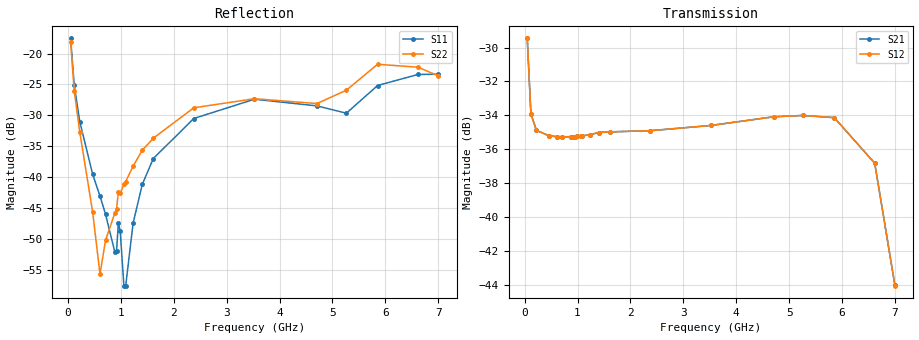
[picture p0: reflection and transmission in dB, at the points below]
! Integrated Device Technology
! Corporate Headquarters
! 6024 Silver Creek Valley Road
! San Jose, CA 95138  USA
! Phone:  1-408-284-8200
! Toll Free:  1-800-223-1366
! Webpage:  http://www.idt.com/
! Timing and RF Division
! 515 Groton Road, Suite 102
! Westford, MA 01886-6024
! Device:  F2258
! Description: Voltage Variable RF Attenuator
! Frequency:  50.0 -  6000.00 MHz
! Package:  3x3 mm Thin QFN Plastic Package: 16 pin
! Ports:  2 RF, 2 DC
!  Pin  1  = NC
!  Pin  2  = NC
!  Pin  3  = RF2  = Port 2
!  Pin  4  = GND
!  Pin  5  = Vdd
!  Pin  6  = NC
!  Pin  7  = VCTRL
!  Pin  8  = NC
!  Pin  9  = GND
!  Pin 10  = RF1  = Port 1
!  Pin 11  = NC
!  Pin 12  = NC
!  Pin 13  = NC
!  Pin 14  = NC
!  Pin 15  = NC
!  Pin 16  = NC
! Vcntrl:  2.120 Volts
! Vdd:  +3.300 Volts
! Current:  1.152 mA
! Data:  The device was measured on a the F2258 evaluation board which has
!  individual transmission lines to the RF pins.  Data was collected
!  using a calibrated network analyzer.  The evaluation board was
!  de-embedded using a TRL calibration technique.
!  The reference plane is the edge of the package pin.
! Misc:  SN 10
!  Action Tracker AT0285
! Date Measured:  2014-12-10
! Date:  2016-01-13  MJV
! Note:
!  Integrated Device Technology supplies this data as a sample of measured
!  data at the package pin for this product.  Your particular data for this
!  product may vary.
!  Data was taken at 25 degrees C.
!  Integrated Device Technology reserves the right to change this data at anytime.
!Freq_(GHz)  S11M_(dB)  S11P_(deg)  S21M_(dB)  S21P_(deg)  S12M_(dB)  S12P_(deg)  S22M_(dB)  S22P_(deg)
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# GHz S dB R 50
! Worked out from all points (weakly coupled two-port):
!   201 points, 50 MHz to 7 GHz, reference 50 ohm
!   highest |S21| = -29.46 dB at 50 MHz (marker M1); lowest = -44.0 dB at 7 GHz (marker M2)
!   lowest |S11| = -57.6 dB at 1.058 GHz (marker M3), VSWR 1.00, Z = 49.9 + j0.0562 ohm
!   |S11| at or under -10 dB: start of sweep to end of sweep
!   |S22| runs from -55.7 to -18.1 dB; largest |S21 - S12| = 6e-05
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0.05  -17.55 -111.0  -29.46 -67.8  -29.46 -67.8  -18.09 -110.2
0.1195  -25.12 -106.9  -33.93 -36.4  -33.93 -36.4  -26.06 -102.1
0.22375  -31.03 -110.6  -34.89 -21.1  -34.89 -21.1  -32.73 -99.9
0.467  -39.54 -120.4  -35.22 -11.8  -35.22 -11.7  -45.65 -84.8
0.606  -43.07 -126.1  -35.26 -10.0  -35.26 -10.0  -55.72 -21.3
0.71025  -46.01 -137.6  -35.27 -9.2  -35.27 -9.2  -50.26 50.4
0.884  -52.05 166.7  -35.26 -8.5  -35.27 -8.5  -45.87 67.6
0.91875  -51.93 150.4  -35.26 -8.4  -35.26 -8.4  -45.16 68.5
0.9535  -47.43 -162.4  -35.27 -8.3  -35.27 -8.3  -42.40 93.6
0.98825  -48.78 -174.0  -35.25 -8.2  -35.25 -8.2  -42.64 89.8
1.05775  -57.58 154.8  -35.23 -8.1  -35.23 -8.1  -41.19 74.4
1.0925  -57.56 119.8  -35.21 -8.0  -35.22 -8.0  -40.72 71.7
1.2315  -47.46 46.8  -35.15 -8.1  -35.14 -8.1  -38.24 55.0
1.40525  -41.19 33.6  -35.02 -8.8  -35.02 -8.7  -35.66 48.3
1.61375  -37.00 32.9  -34.98 -9.8  -34.98 -9.8  -33.71 39.5
2.37825  -30.52 48.2  -34.91 -13.5  -34.91 -13.5  -28.79 35.5
3.525  -27.40 91.7  -34.60 -20.0  -34.60 -20.1  -27.32 61.8
4.7065  -28.48 95.6  -34.09 -29.3  -34.09 -29.2  -28.10 53.4
5.2625  -29.66 54.4  -34.01 -35.4  -34.01 -35.3  -25.94 16.0
5.85325  -25.18 29.8  -34.14 -45.9  -34.14 -45.9  -21.74 -5.8
6.61775  -23.39 49.7  -36.83 -68.8  -36.83 -68.7  -22.22 -47.0
7  -23.37 84.5  -44.04 -61.9  -44.06 -61.6  -23.62 -129.1
